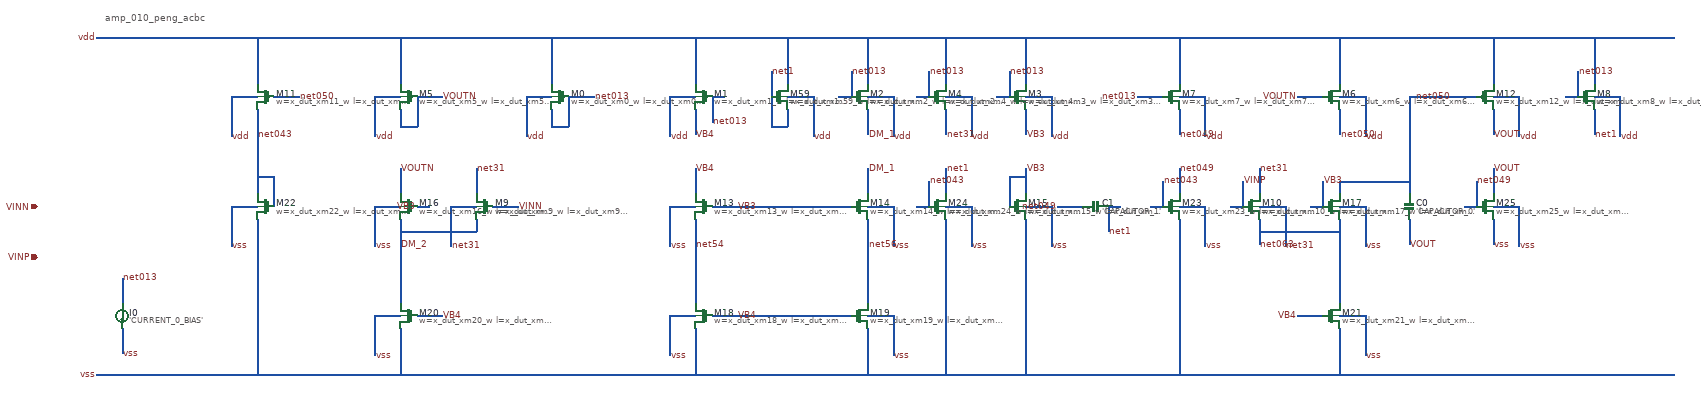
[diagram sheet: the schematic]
v {xschem version=3.4.6 file_version=1.2}
G {}
K {}
V {}
S {}
E {}
T {amp_010_peng_acbc} -1740 -200 0 0 0.4 0.4 {}
C {devices/capa_np.sym} 1355 260 0 0 {name=C0 value='CAPACITOR_0'}
C {devices/capa_np.sym} 610 260 1 0 {name=C1 value='CAPACITOR_1'}
C {devices/isource_np.sym} -1700 520 0 0 {name=I0 value='CURRENT_0_BIAS'}
C {devices/sg13_lv_pmos_np.sym} -660 0 0 1 {name=M0 model=sg13_lv_pmos spiceprefix=X w=x_dut_xm0_w l=x_dut_xm0_l m=x_dut_xm0_m}
C {devices/sg13_lv_pmos_np.sym} -320 0 0 1 {name=M1 model=sg13_lv_pmos spiceprefix=X w=x_dut_xm1_w l=x_dut_xm1_l m=x_dut_xm1_m}
C {devices/sg13_lv_pmos_np.sym} 980 260 0 0 {name=M10 model=sg13_lv_pmos spiceprefix=X w=x_dut_xm10_w l=x_dut_xm10_l m=x_dut_xm10_m}
C {devices/sg13_lv_pmos_np.sym} -1360 0 0 1 {name=M11 model=sg13_lv_pmos spiceprefix=X w=x_dut_xm11_w l=x_dut_xm11_l m=x_dut_xm11_m}
C {devices/sg13_lv_pmos_np.sym} 1535 0 0 0 {name=M12 model=sg13_lv_pmos spiceprefix=X w=x_dut_xm12_w l=x_dut_xm12_l m=x_dut_xm12_m}
C {devices/sg13_lv_nmos_np.sym} -320 260 0 1 {name=M13 model=sg13_lv_nmos spiceprefix=X w=x_dut_xm13_w l=x_dut_xm13_l m=x_dut_xm13_m}
C {devices/sg13_lv_nmos_np.sym} 50 260 0 0 {name=M14 model=sg13_lv_nmos spiceprefix=X w=x_dut_xm14_w l=x_dut_xm14_l m=x_dut_xm14_m}
C {devices/sg13_lv_nmos_np.sym} 425 260 0 0 {name=M15 model=sg13_lv_nmos spiceprefix=X w=x_dut_xm15_w l=x_dut_xm15_l m=x_dut_xm15_m}
C {devices/sg13_lv_nmos_np.sym} -1020 260 0 1 {name=M16 model=sg13_lv_nmos spiceprefix=X w=x_dut_xm16_w l=x_dut_xm16_l m=x_dut_xm16_m}
C {devices/sg13_lv_nmos_np.sym} 1170 260 0 0 {name=M17 model=sg13_lv_nmos spiceprefix=X w=x_dut_xm17_w l=x_dut_xm17_l m=x_dut_xm17_m}
C {devices/sg13_lv_nmos_np.sym} -320 520 0 1 {name=M18 model=sg13_lv_nmos spiceprefix=X w=x_dut_xm18_w l=x_dut_xm18_l m=x_dut_xm18_m}
C {devices/sg13_lv_nmos_np.sym} 50 520 0 0 {name=M19 model=sg13_lv_nmos spiceprefix=X w=x_dut_xm19_w l=x_dut_xm19_l m=x_dut_xm19_m}
C {devices/sg13_lv_pmos_np.sym} 50 0 0 0 {name=M2 model=sg13_lv_pmos spiceprefix=X w=x_dut_xm2_w l=x_dut_xm2_l m=x_dut_xm2_m}
C {devices/sg13_lv_nmos_np.sym} -1020 520 0 1 {name=M20 model=sg13_lv_nmos spiceprefix=X w=x_dut_xm20_w l=x_dut_xm20_l m=x_dut_xm20_m}
C {devices/sg13_lv_nmos_np.sym} 1170 520 0 0 {name=M21 model=sg13_lv_nmos spiceprefix=X w=x_dut_xm21_w l=x_dut_xm21_l m=x_dut_xm21_m}
C {devices/sg13_lv_nmos_np.sym} -1360 260 0 1 {name=M22 model=sg13_lv_nmos spiceprefix=X w=x_dut_xm22_w l=x_dut_xm22_l m=x_dut_xm22_m}
C {devices/sg13_lv_nmos_np.sym} 790 260 0 0 {name=M23 model=sg13_lv_nmos spiceprefix=X w=x_dut_xm23_w l=x_dut_xm23_l m=x_dut_xm23_m}
C {devices/sg13_lv_nmos_np.sym} 235 260 0 0 {name=M24 model=sg13_lv_nmos spiceprefix=X w=x_dut_xm24_w l=x_dut_xm24_l m=x_dut_xm24_m}
C {devices/sg13_lv_nmos_np.sym} 1535 260 0 0 {name=M25 model=sg13_lv_nmos spiceprefix=X w=x_dut_xm25_w l=x_dut_xm25_l m=x_dut_xm25_m}
C {devices/sg13_lv_pmos_np.sym} 425 0 0 0 {name=M3 model=sg13_lv_pmos spiceprefix=X w=x_dut_xm3_w l=x_dut_xm3_l m=x_dut_xm3_m}
C {devices/sg13_lv_pmos_np.sym} 235 0 0 0 {name=M4 model=sg13_lv_pmos spiceprefix=X w=x_dut_xm4_w l=x_dut_xm4_l m=x_dut_xm4_m}
C {devices/sg13_lv_pmos_np.sym} -1020 0 0 1 {name=M5 model=sg13_lv_pmos spiceprefix=X w=x_dut_xm5_w l=x_dut_xm5_l m=x_dut_xm5_m}
C {devices/sg13_lv_pmos_np.sym} -140 0 0 0 {name=M59 model=sg13_lv_pmos spiceprefix=X w=x_dut_xm59_w l=x_dut_xm59_l m=x_dut_xm59_m}
C {devices/sg13_lv_pmos_np.sym} 1170 0 0 0 {name=M6 model=sg13_lv_pmos spiceprefix=X w=x_dut_xm6_w l=x_dut_xm6_l m=x_dut_xm6_m}
C {devices/sg13_lv_pmos_np.sym} 790 0 0 0 {name=M7 model=sg13_lv_pmos spiceprefix=X w=x_dut_xm7_w l=x_dut_xm7_l m=x_dut_xm7_m}
C {devices/sg13_lv_pmos_np.sym} 1775 0 0 0 {name=M8 model=sg13_lv_pmos spiceprefix=X w=x_dut_xm8_w l=x_dut_xm8_l m=x_dut_xm8_m}
C {devices/sg13_lv_pmos_np.sym} -840 260 0 1 {name=M9 model=sg13_lv_pmos spiceprefix=X w=x_dut_xm9_w l=x_dut_xm9_l m=x_dut_xm9_m}
N -1700 430 -1700 490 {}
N -1700 550 -1700 610 {}
N -1440 0 -1440 94 {}
N -1440 260 -1440 354 {}
N -1380 -140 -1380 -30 {}
N -1380 30 -1380 230 {}
N -1380 290 -1380 660 {}
N -1340 190 -1340 260 {}
N -1100 0 -1100 94 {}
N -1100 260 -1100 354 {}
N -1100 520 -1100 614 {}
N -1040 -140 -1040 -30 {}
N -1040 30 -1040 70 {}
N -1040 170 -1040 230 {}
N -1040 290 -1040 490 {}
N -1040 550 -1040 660 {}
N -1000 0 -1000 70 {}
N -920 260 -920 354 {}
N -860 170 -860 230 {}
N -860 290 -860 320 {}
N -740 0 -740 94 {}
N -680 -140 -680 -30 {}
N -680 30 -680 70 {}
N -640 0 -640 70 {}
N -400 0 -400 94 {}
N -400 260 -400 354 {}
N -400 520 -400 614 {}
N -340 -140 -340 -30 {}
N -340 30 -340 90 {}
N -340 170 -340 230 {}
N -340 290 -340 490 {}
N -340 550 -340 660 {}
N -300 0 -300 60 {}
N -160 -60 -160 70 {}
N -120 -140 -120 -30 {}
N -120 30 -120 70 {}
N -60 0 -60 94 {}
N 30 -60 30 0 {}
N 70 -140 70 -30 {}
N 70 30 70 90 {}
N 70 170 70 230 {}
N 70 290 70 490 {}
N 70 550 70 660 {}
N 130 0 130 94 {}
N 130 260 130 354 {}
N 130 520 130 614 {}
N 215 -60 215 0 {}
N 215 200 215 260 {}
N 255 -140 255 -30 {}
N 255 30 255 90 {}
N 255 170 255 230 {}
N 255 290 255 660 {}
N 315 0 315 94 {}
N 315 260 315 354 {}
N 405 -60 405 0 {}
N 405 190 405 260 {}
N 445 -140 445 -30 {}
N 445 30 445 90 {}
N 445 170 445 230 {}
N 445 290 445 660 {}
N 505 0 505 94 {}
N 505 260 505 354 {}
N 640 260 640 320 {}
N 770 200 770 260 {}
N 810 -140 810 -30 {}
N 810 30 810 90 {}
N 810 170 810 230 {}
N 810 290 810 660 {}
N 870 0 870 94 {}
N 870 260 870 354 {}
N 960 200 960 260 {}
N 1000 170 1000 230 {}
N 1000 290 1000 350 {}
N 1060 260 1060 354 {}
N 1150 200 1150 260 {}
N 1190 -140 1190 -30 {}
N 1190 30 1190 90 {}
N 1190 200 1190 230 {}
N 1190 290 1190 490 {}
N 1190 550 1190 660 {}
N 1250 0 1250 94 {}
N 1250 260 1250 354 {}
N 1250 520 1250 614 {}
N 1355 0 1355 230 {}
N 1355 290 1355 350 {}
N 1515 200 1515 260 {}
N 1555 -140 1555 -30 {}
N 1555 30 1555 90 {}
N 1555 170 1555 230 {}
N 1555 290 1555 350 {}
N 1615 0 1615 94 {}
N 1615 260 1615 354 {}
N 1755 -60 1755 0 {}
N 1795 -140 1795 -30 {}
N 1795 30 1795 90 {}
N 1855 0 1855 94 {}
N -1760 -140 1985 -140 {}
N -1440 0 -1380 0 {}
N -1340 0 -1280 0 {}
N -1100 0 -1040 0 {}
N -1000 0 -940 0 {}
N -740 0 -680 0 {}
N -640 0 -580 0 {}
N -400 0 -340 0 {}
N -300 0 -270 0 {}
N -120 0 -60 0 {}
N 0 0 30 0 {}
N 70 0 130 0 {}
N 185 0 215 0 {}
N 255 0 315 0 {}
N 375 0 405 0 {}
N 445 0 505 0 {}
N 710 0 770 0 {}
N 810 0 870 0 {}
N 1090 0 1150 0 {}
N 1190 0 1250 0 {}
N 1355 0 1515 0 {}
N 1555 0 1615 0 {}
N 1725 0 1755 0 {}
N 1795 0 1855 0 {}
N -1040 70 -1000 70 {}
N -680 70 -640 70 {}
N -160 70 -120 70 {}
N -1380 190 -1340 190 {}
N 405 190 445 190 {}
N 1190 200 1355 200 {}
N -1440 260 -1380 260 {}
N -1100 260 -1040 260 {}
N -1000 260 -970 260 {}
N -920 260 -860 260 {}
N -820 260 -760 260 {}
N -400 260 -340 260 {}
N -300 260 30 260 {}
N 70 260 130 260 {}
N 185 260 215 260 {}
N 255 260 315 260 {}
N 445 260 505 260 {}
N 520 260 580 260 {}
N 640 260 670 260 {}
N 740 260 770 260 {}
N 810 260 870 260 {}
N 930 260 960 260 {}
N 1000 260 1060 260 {}
N 1120 260 1150 260 {}
N 1190 260 1250 260 {}
N 1485 260 1515 260 {}
N 1555 260 1615 260 {}
N -1040 320 -860 320 {}
N 1000 320 1190 320 {}
N -1100 520 -1040 520 {}
N -1000 520 -940 520 {}
N -400 520 -340 520 {}
N -300 520 30 520 {}
N 70 520 130 520 {}
N 1090 520 1150 520 {}
N 1190 520 1250 520 {}
N -1760 660 1985 660 {}
C {devices/lab_wire.sym} -1760 -140 0 0 {name=l0 lab=vdd}
C {devices/lab_wire.sym} -1760 660 0 0 {name=l1 lab=vss}
C {devices/lab_wire.sym} 70 90 2 0 {name=l2 lab=DM_1}
C {devices/lab_wire.sym} 70 170 0 1 {name=l3 lab=DM_1}
C {devices/lab_wire.sym} -1040 350 2 0 {name=l4 lab=DM_2}
C {devices/lab_wire.sym} -1000 260 0 0 {name=l5 lab=VB3}
C {devices/lab_wire.sym} -240 260 0 1 {name=l6 lab=VB3}
C {devices/lab_wire.sym} 445 170 0 1 {name=l7 lab=VB3}
C {devices/lab_wire.sym} 445 90 2 0 {name=l8 lab=VB3}
C {devices/lab_wire.sym} 1150 200 0 1 {name=l9 lab=VB3}
C {devices/lab_wire.sym} -940 520 0 1 {name=l10 lab=VB4}
C {devices/lab_wire.sym} -340 90 2 0 {name=l11 lab=VB4}
C {devices/lab_wire.sym} -340 170 0 1 {name=l12 lab=VB4}
C {devices/lab_wire.sym} -240 520 0 1 {name=l13 lab=VB4}
C {devices/lab_wire.sym} 1090 520 0 0 {name=l14 lab=VB4}
C {devices/lab_wire.sym} -760 260 0 1 {name=l15 lab=VINN}
C {devices/lab_wire.sym} 960 200 0 1 {name=l16 lab=VINP}
C {devices/lab_wire.sym} 1355 350 2 0 {name=l17 lab=VOUT}
C {devices/lab_wire.sym} 1555 90 2 0 {name=l18 lab=VOUT}
C {devices/lab_wire.sym} 1555 170 0 1 {name=l19 lab=VOUT}
C {devices/lab_wire.sym} -940 0 0 1 {name=l20 lab=VOUTN}
C {devices/lab_wire.sym} -1040 170 0 1 {name=l21 lab=VOUTN}
C {devices/lab_wire.sym} 1090 0 0 0 {name=l22 lab=VOUTN}
C {devices/lab_wire.sym} -580 0 0 1 {name=l23 lab=net013}
C {devices/lab_wire.sym} -300 60 2 0 {name=l24 lab=net013}
C {devices/lab_wire.sym} 30 -60 0 1 {name=l25 lab=net013}
C {devices/lab_wire.sym} 215 -60 0 1 {name=l26 lab=net013}
C {devices/lab_wire.sym} 405 -60 0 1 {name=l27 lab=net013}
C {devices/lab_wire.sym} 710 0 0 0 {name=l28 lab=net013}
C {devices/lab_wire.sym} 1755 -60 0 1 {name=l29 lab=net013}
C {devices/lab_wire.sym} -1380 90 2 0 {name=l30 lab=net043}
C {devices/lab_wire.sym} 215 200 0 1 {name=l31 lab=net043}
C {devices/lab_wire.sym} 770 200 0 1 {name=l32 lab=net043}
C {devices/lab_wire.sym} 520 260 0 0 {name=l33 lab=net049}
C {devices/lab_wire.sym} 810 90 2 0 {name=l34 lab=net049}
C {devices/lab_wire.sym} 810 170 0 1 {name=l35 lab=net049}
C {devices/lab_wire.sym} 1515 200 0 1 {name=l36 lab=net049}
C {devices/lab_wire.sym} -1280 0 0 1 {name=l37 lab=net050}
C {devices/lab_wire.sym} 1190 90 2 0 {name=l38 lab=net050}
C {devices/lab_wire.sym} 1455 0 0 0 {name=l39 lab=net050}
C {devices/lab_wire.sym} 1000 350 2 0 {name=l40 lab=net063}
C {devices/lab_wire.sym} -160 -60 0 1 {name=l41 lab=net1}
C {devices/lab_wire.sym} 255 170 0 1 {name=l42 lab=net1}
C {devices/lab_wire.sym} 640 320 2 0 {name=l43 lab=net1}
C {devices/lab_wire.sym} 1795 90 2 0 {name=l44 lab=net1}
C {devices/lab_wire.sym} -860 170 0 1 {name=l45 lab=net31}
C {devices/lab_wire.sym} 255 90 2 0 {name=l46 lab=net31}
C {devices/lab_wire.sym} 1000 170 0 1 {name=l47 lab=net31}
C {devices/lab_wire.sym} -340 350 2 0 {name=l48 lab=net54}
C {devices/lab_wire.sym} 70 350 2 0 {name=l49 lab=net56}
C {devices/lab_wire.sym} 1060 354 2 0 {name=l50 lab=net31}
C {devices/lab_wire.sym} -920 354 2 0 {name=l51 lab=net31}
C {devices/lab_wire.sym} -740 94 2 0 {name=l52 lab=vdd}
C {devices/lab_wire.sym} -400 94 2 0 {name=l53 lab=vdd}
C {devices/lab_wire.sym} -1440 94 2 0 {name=l54 lab=vdd}
C {devices/lab_wire.sym} 1615 94 2 0 {name=l55 lab=vdd}
C {devices/lab_wire.sym} 130 94 2 0 {name=l56 lab=vdd}
C {devices/lab_wire.sym} 505 94 2 0 {name=l57 lab=vdd}
C {devices/lab_wire.sym} 315 94 2 0 {name=l58 lab=vdd}
C {devices/lab_wire.sym} -1100 94 2 0 {name=l59 lab=vdd}
C {devices/lab_wire.sym} -60 94 2 0 {name=l60 lab=vdd}
C {devices/lab_wire.sym} 1250 94 2 0 {name=l61 lab=vdd}
C {devices/lab_wire.sym} 870 94 2 0 {name=l62 lab=vdd}
C {devices/lab_wire.sym} 1855 94 2 0 {name=l63 lab=vdd}
C {devices/lab_wire.sym} -400 354 2 0 {name=l64 lab=vss}
C {devices/lab_wire.sym} 130 354 2 0 {name=l65 lab=vss}
C {devices/lab_wire.sym} 505 354 2 0 {name=l66 lab=vss}
C {devices/lab_wire.sym} -1100 354 2 0 {name=l67 lab=vss}
C {devices/lab_wire.sym} 1250 354 2 0 {name=l68 lab=vss}
C {devices/lab_wire.sym} -400 614 2 0 {name=l69 lab=vss}
C {devices/lab_wire.sym} 130 614 2 0 {name=l70 lab=vss}
C {devices/lab_wire.sym} -1100 614 2 0 {name=l71 lab=vss}
C {devices/lab_wire.sym} 1250 614 2 0 {name=l72 lab=vss}
C {devices/lab_wire.sym} -1440 354 2 0 {name=l73 lab=vss}
C {devices/lab_wire.sym} 870 354 2 0 {name=l74 lab=vss}
C {devices/lab_wire.sym} 315 354 2 0 {name=l75 lab=vss}
C {devices/lab_wire.sym} 1615 354 2 0 {name=l76 lab=vss}
C {devices/lab_wire.sym} -1700 430 0 1 {name=l77 lab=net013}
C {devices/lab_wire.sym} -1700 610 2 0 {name=l78 lab=vss}
C {devices/lab_wire.sym} 1555 350 2 0 {name=l79 lab=vss}
C {devices/ipin.sym} -1900 260 0 0 {name=p0 lab=VINN}
C {devices/ipin.sym} -1900 380 0 0 {name=p1 lab=VINP}
